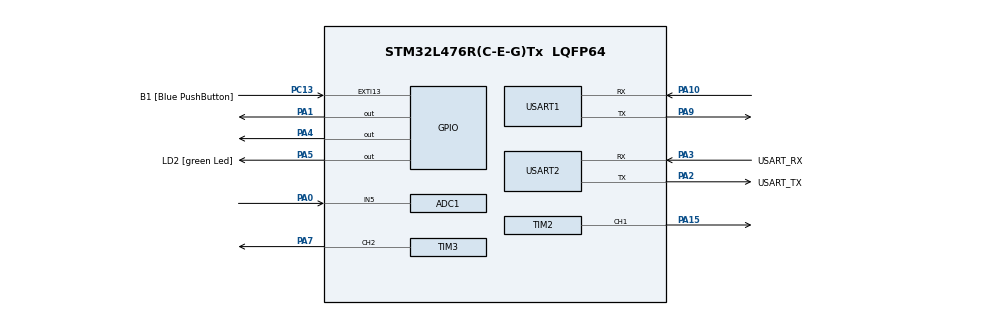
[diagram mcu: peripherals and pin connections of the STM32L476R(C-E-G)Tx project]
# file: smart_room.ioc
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ADC1.Channel-0\#ChannelRegularConversion=ADC_CHANNEL_5
ADC1.NbrOfConversionFlag=1
ADC1.OffsetNumber-0\#ChannelRegularConversion=ADC_OFFSET_NONE
ADC1.Rank-0\#ChannelRegularConversion=1
ADC1.SamplingTime-0\#ChannelRegularConversion=ADC_SAMPLETIME_2CYCLES_5
ADC1.master=1
FREERTOS.Tasks01=defaultTask,0,128,StartDefaultTask,Default,NULL,Dynamic,NULL,NULL
FREERTOS.configUSE_NEWLIB_REENTRANT=1
Mcu.Family=STM32L4
Mcu.Name=STM32L476R(C-E-G)Tx
Mcu.Package=LQFP64
NVIC.PriorityGroup=NVIC_PRIORITYGROUP_4
NVIC.TIM1_UP_TIM16_IRQn=true\:15\:0\:false\:false\:true\:false\:false\:true
NVIC.TIM2_IRQn=true\:5\:0\:false\:false\:true\:true\:true\:true
NVIC.TIM3_IRQn=true\:5\:0\:false\:false\:true\:true\:true\:true
NVIC.TimeBase=TIM1_UP_TIM16_IRQn
NVIC.TimeBaseIP=TIM1
NVIC.USART1_IRQn=true\:5\:0\:false\:false\:true\:true\:true\:true
NVIC.USART2_IRQn=true\:5\:0\:false\:false\:true\:true\:true\:true
PA0.Signal=ADCx_IN5
PA1.PinState=GPIO_PIN_SET
PA1.Signal=GPIO_Output
PA10.Mode=Asynchronous
PA10.Signal=USART1_RX
PA13\ (JTMS-SWDIO).GPIO_Label=TMS
PA13\ (JTMS-SWDIO).Mode=Serial_Wire
PA13\ (JTMS-SWDIO).Signal=SYS_JTMS-SWDIO
PA14\ (JTCK-SWCLK).GPIO_Label=TCK
PA14\ (JTCK-SWCLK).Mode=Serial_Wire
PA14\ (JTCK-SWCLK).Signal=SYS_JTCK-SWCLK
PA15\ (JTDI).Signal=S_TIM2_CH1
PA2.GPIO_Label=USART_TX
PA2.GPIO_Mode=GPIO_MODE_AF_PP
PA2.GPIO_PuPd=GPIO_NOPULL
PA2.GPIO_Speed=GPIO_SPEED_FREQ_VERY_HIGH
PA2.Mode=Asynchronous
PA2.Signal=USART2_TX
PA3.GPIO_Label=USART_RX
PA3.GPIO_Mode=GPIO_MODE_AF_PP
PA3.GPIO_PuPd=GPIO_NOPULL
PA3.GPIO_Speed=GPIO_SPEED_FREQ_VERY_HIGH
PA3.Mode=Asynchronous
PA3.Signal=USART2_RX
PA4.Signal=GPIO_Output
PA5.GPIO_Label=LD2 [green Led]
PA5.GPIO_ModeDefaultOutputPP=GPIO_MODE_OUTPUT_PP
PA5.GPIO_PuPd=GPIO_NOPULL
PA5.GPIO_Speed=GPIO_SPEED_FREQ_LOW
PA5.Signal=GPIO_Output
PA7.Signal=S_TIM3_CH2
PA9.Mode=Asynchronous
PA9.Signal=USART1_TX
PB3\ (JTDO-TRACESWO).GPIO_Label=SWO
PB3\ (JTDO-TRACESWO).Signal=SYS_JTDO-SWO
PC13.GPIO_Label=B1 [Blue PushButton]
PC13.GPIO_ModeDefaultEXTI=GPIO_MODE_IT_FALLING
PC13.GPIO_PuPd=GPIO_NOPULL
PC13.Signal=GPXTI13
PC14-OSC32_IN\ (PC14).Mode=LSE-External-Oscillator
PC14-OSC32_IN\ (PC14).Signal=RCC_OSC32_IN
PC15-OSC32_OUT\ (PC15).Mode=LSE-External-Oscillator
PC15-OSC32_OUT\ (PC15).Signal=RCC_OSC32_OUT
PH0-OSC_IN\ (PH0).Signal=RCC_OSC_IN
PH1-OSC_OUT\ (PH1).Signal=RCC_OSC_OUT
ProjectManager.HeapSize=0x200
ProjectManager.StackSize=0x400
ProjectManager.TargetToolchain=STM32CubeIDE
RCC.ADCFreq_Value=64000000
RCC.AHBCLKDivider=RCC_SYSCLK_DIV2
RCC.AHBFreq_Value=8000000
RCC.APB1Freq_Value=8000000
RCC.APB1TimFreq_Value=8000000
RCC.APB2CLKDivider=RCC_HCLK_DIV16
RCC.APB2Freq_Value=500000
RCC.APB2TimFreq_Value=1000000
RCC.CortexFreq_Value=8000000
RCC.HCLKFreq_Value=8000000
RCC.HSE_VALUE=8000000
RCC.HSI_VALUE=16000000
RCC.MSI_VALUE=4000000
RCC.PLLN=10
RCC.PLLSourceVirtual=RCC_PLLSOURCE_HSI
RCC.PREFETCH_ENABLE=1
RCC.SYSCLKFreq_VALUE=16000000
RCC.SYSCLKSource=RCC_SYSCLKSOURCE_HSI
RCC.USBFreq_Value=64000000
RCC.VCOOutputFreq_Value=160000000
SH.ADCx_IN5.0=ADC1_IN5,IN5-Single-Ended
SH.S_TIM2_CH1.0=TIM2_CH1,PWM Generation1 CH1
SH.S_TIM3_CH2.0=TIM3_CH2,PWM Generation2 CH2
TIM2.Channel-PWM\ Generation1\ CH1=TIM_CHANNEL_1
TIM2.Period=2000-1
TIM2.Prescaler=127
TIM3.Channel-PWM\ Generation2\ CH2=TIM_CHANNEL_2
TIM3.Period=1000
TIM3.Prescaler=19
TIM3.Pulse-PWM\ Generation2\ CH2=500
USART1.VirtualMode-Asynchronous=VM_ASYNC
USART2.VirtualMode-Asynchronous=VM_ASYNC
VP_FREERTOS_VS_CMSIS_V1.Mode=CMSIS_V1
VP_SYS_VS_tim1.Mode=TIM1
VP_TIM2_VS_ClockSourceINT.Mode=Internal
VP_TIM3_VS_ClockSourceINT.Mode=Internal
board=NUCLEO-L476RG

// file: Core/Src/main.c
/* USER CODE BEGIN Header */
/**
  ******************************************************************************
  * @file           : main.c
  * @brief          : Main program body
  ******************************************************************************
  * @attention
  *
  * <h2><center>&copy; Copyright (c) 2021 STMicroelectronics.
  * All rights reserved.</center></h2>
  *
  * This software component is licensed by ST under BSD 3-Clause license,
  * the "License"; You may not use this file except in compliance with the
  * License. You may obtain a copy of the License at:
  *                        opensource.org/licenses/BSD-3-Clause
  *
  ******************************************************************************
  */
/* USER CODE END Header */
#include "main.h"
#include "cmsis_os.h"

ADC_HandleTypeDef hadc1;

TIM_HandleTypeDef htim2;
TIM_HandleTypeDef htim3;

osThreadId defaultTaskHandle;

void SystemClock_Config(void);
static void MX_GPIO_Init(void);
static void MX_USART2_UART_Init(void);
static void MX_ADC1_Init(void);
static void MX_USART1_UART_Init(void);
static void MX_TIM3_Init(void);
static void MX_TIM2_Init(void);
void StartDefaultTask(void const * argument);

/* USER CODE BEGIN PFP */
void changeLedState(uint8_t mode);
int8_t readVoltage(void);
void changeDoorState(uint8_t mode);
void changeAlarmState(uint8_t mode);
/* USER CODE END PFP */

/* USER CODE BEGIN 0 */
//Tamanho das filas de transmissao e recepcao
//A fila de transmissao é maior do que a de recepcao por que a rotina de transmissao (write_string)
//pode enfileirar um numero maior de bytes de forma muito rapida
#define TX_QUEUE_SIZE 128
#define RX_QUEUE_SIZE 5
#define TIMER_MAX 200
#define USART_1 1
#define USART_2 2

//Variaveis que irao armazenar os hanldes das filas de tranmissao e recepcao
QueueHandle_t tx_queue_1;
QueueHandle_t rx_queue_1;
QueueHandle_t tx_queue_2;
QueueHandle_t rx_queue_2;
SemaphoreHandle_t uart_1_mutex = NULL;
SemaphoreHandle_t uart_2_mutex = NULL;
uint8_t door_state = 1;
uint8_t timer = 0;
uint8_t alarm_ring = 0;
uint8_t alarm_state = 0;

void sendchar(char c, char usart){
	if(usart == USART_1){
		xQueueSend(tx_queue_1, &c, HAL_MAX_DELAY);
		LL_USART_EnableIT_TXE(USART1);
	}
	else if( usart == USART_2){
		xQueueSend(tx_queue_2, &c, HAL_MAX_DELAY);
		LL_USART_EnableIT_TXE(USART2);
	}
}

void sendString(char * str, char usart){
	while(*str != 0){
		sendchar(*str, usart);
		str++;
	}
}

char readchar(char usart){
	uint8_t caracter=0;
	if(usart == USART_1)
		xQueueReceive(rx_queue_1, &caracter, HAL_MAX_DELAY);
	else if(usart == USART_2)
		xQueueReceive(rx_queue_2, &caracter, HAL_MAX_DELAY);
	return caracter;
}

void cli(void * vParam)
{
	uint8_t caracter;
	while(1)
	{
		caracter = readchar(USART_1);

		char buff[8];
		uint8_t temp = readVoltage();
		sprintf(buff,"\n%d\r\n", temp);
		sendString(buff, USART_1);

		switch(caracter){
					case 'L':
						changeLedState(1);
						break;
					case 'D':
						changeLedState(0);
						break;
					case 'O':
						changeDoorState(1);
						break;
					case 'C':
						changeDoorState(0);
						break;
					case 'A':
						changeAlarmState(1);
						break;
					case 'Z':
						changeAlarmState(0);
						break;
				}
	}

}

void changeLedState(uint8_t mode){
	HAL_GPIO_WritePin(LD2_GPIO_Port, LD2_Pin, mode);
}

void changeAlarmState(uint8_t mode){
	if(mode == 1){
		alarm_state = mode;
		timer = 1;
		HAL_TIM_Base_Start_IT(&htim2);
	} else {
		alarm_state = 0;
	}
}

int8_t readVoltage(void){
	HAL_ADC_Start(&hadc1);
	HAL_ADC_PollForConversion(&hadc1, HAL_MAX_DELAY);
	return HAL_ADC_GetValue(&hadc1) / 25;
}

void changeDoorState(uint8_t mode){
	if(mode == 1 && door_state == 0){
		HAL_TIM_PWM_Start(&htim3,TIM_CHANNEL_2);
		__HAL_TIM_SetCompare(&htim3, TIM_CHANNEL_2, 100);
		vTaskDelay(500);
		HAL_TIM_PWM_Stop(&htim3,TIM_CHANNEL_2);
		door_state = 1;

	} else if(mode == 0 && door_state == 1){
		HAL_TIM_PWM_Start(&htim3,TIM_CHANNEL_2);
		__HAL_TIM_SetCompare(&htim3, TIM_CHANNEL_2, 50);
		vTaskDelay(500);
		HAL_TIM_PWM_Stop(&htim3,TIM_CHANNEL_2);
		door_state = 0;
	}
}

//Rotina de tratamento de interrupcao da USART2
void USART_2_IRQHandler(void)
{
	//Se for interrupcao de transmissao
    if (LL_USART_IsActiveFlag_TXE(USART2)) {
        BaseType_t contextSwitch;

        while (LL_USART_IsActiveFlag_TXE(USART2)) {
            uint8_t byte;
            //Desinfileira um byte para tranmistir
            if (xQueueReceiveFromISR(tx_queue_2, &byte, &contextSwitch) == pdFAIL) {
            	//Se a fila de transmissao esta vazia, encerra a transmissao
                LL_USART_DisableIT_TXE(USART2);
                break;
            }
            //Envia o byte retirado da fila de transmisao
            LL_USART_TransmitData8(USART2, byte);
        }
        portYIELD_FROM_ISR(contextSwitch);
    }

    //Se for interrupcao de recepcao
    if (LL_USART_IsActiveFlag_RXNE(USART2)) {
        BaseType_t contextSwitch;

        while (LL_USART_IsActiveFlag_RXNE(USART2)) {
        	//Copia o byte do regstrador de recepcao
        	uint8_t byte =
                LL_USART_ReceiveData8(USART2);
        	//Enfileira o byte recebido na fila de recepcao
            xQueueSendFromISR(rx_queue_2, &byte, &contextSwitch);
            // xQueueSendFromISR can return errQUEUE_FULL
        }
        portYIELD_FROM_ISR(contextSwitch);
    }
}

void USART_1_IRQHandler(void)
{
	//Se for interrupcao de transmissao
    if (LL_USART_IsActiveFlag_TXE(USART1)) {
        BaseType_t contextSwitch;

        while (LL_USART_IsActiveFlag_TXE(USART1)) {
            uint8_t byte;
            //Desinfileira um byte para tranmistir
            if (xQueueReceiveFromISR(tx_queue_1, &byte, &contextSwitch) == pdFAIL) {
            	//Se a fila de transmissao esta vazia, encerra a transmissao
                LL_USART_DisableIT_TXE(USART1);
                break;
            }
            //Envia o byte retirado da fila de transmisao
            LL_USART_TransmitData8(USART1, byte);
        }
        portYIELD_FROM_ISR(contextSwitch);
    }

    //Se for interrupcao de recepcao
    if (LL_USART_IsActiveFlag_RXNE(USART1)) {
        BaseType_t contextSwitch;

        while (LL_USART_IsActiveFlag_RXNE(USART1)) {
        	//Copia o byte do regstrador de recepcao
        	uint8_t byte =
                LL_USART_ReceiveData8(USART1);
        	//Enfileira o byte recebido na fila de recepcao
            xQueueSendFromISR(rx_queue_1, &byte, &contextSwitch);
            // xQueueSendFromISR can return errQUEUE_FULL
        }
        portYIELD_FROM_ISR(contextSwitch);
    }
}
/* USER CODE END 0 */

int main(void)
{

  /* MCU Configuration--------------------------------------------------------*/

  /* Reset of all peripherals, Initializes the Flash interface and the Systick. */
  HAL_Init();

  /* Configure the system clock */
  SystemClock_Config();

  /* Initialize all configured peripherals */
  MX_GPIO_Init();
  MX_USART2_UART_Init();
  MX_ADC1_Init();
  MX_USART1_UART_Init();
  MX_TIM3_Init();
  MX_TIM2_Init();
  /* USER CODE BEGIN 2 */
  uart_1_mutex = xSemaphoreCreateMutex();
  uart_2_mutex = xSemaphoreCreateMutex();

  HAL_TIM_Base_Start(&htim3);

  /* USER CODE END 2 */

  /* Create the thread(s) */
  /* definition and creation of defaultTask */
  osThreadDef(defaultTask, StartDefaultTask, osPriorityNormal, 0, 128);
  defaultTaskHandle = osThreadCreate(osThread(defaultTask), NULL);

  /* USER CODE BEGIN RTOS_THREADS */
  xTaskCreate(cli,    /* Nome da funcao que contem a task */
  		  	  "cli",     /* Nome descritivo */
			  configMINIMAL_STACK_SIZE,   /* tamanho da pilha da task */
			  NULL,       /* parametro para a task */
			  1,          /* nivel de prioridade */
			  NULL);      /* ponteiro para o handle da task */

  /* USER CODE END RTOS_THREADS */

  /* Start scheduler */
  osKernelStart();

  /* We should never get here as control is now taken by the scheduler */
  /* Infinite loop */
  while (1)
  {

  }
}

void SystemClock_Config(void)
{
  RCC_OscInitTypeDef RCC_OscInitStruct = {0};
  RCC_ClkInitTypeDef RCC_ClkInitStruct = {0};

  /** Configure the main internal regulator output voltage
  */
  if (HAL_PWREx_ControlVoltageScaling(PWR_REGULATOR_VOLTAGE_SCALE1) != HAL_OK)
  {
    Error_Handler();
  }
  /** Initializes the RCC Oscillators according to the specified parameters
  * in the RCC_OscInitTypeDef structure.
  */
  RCC_OscInitStruct.OscillatorType = RCC_OSCILLATORTYPE_HSI;
  RCC_OscInitStruct.HSIState = RCC_HSI_ON;
  RCC_OscInitStruct.HSICalibrationValue = RCC_HSICALIBRATION_DEFAULT;
  RCC_OscInitStruct.PLL.PLLState = RCC_PLL_ON;
  RCC_OscInitStruct.PLL.PLLSource = RCC_PLLSOURCE_HSI;
  RCC_OscInitStruct.PLL.PLLM = 1;
  RCC_OscInitStruct.PLL.PLLN = 10;
  RCC_OscInitStruct.PLL.PLLP = RCC_PLLP_DIV7;
  RCC_OscInitStruct.PLL.PLLQ = RCC_PLLQ_DIV2;
  RCC_OscInitStruct.PLL.PLLR = RCC_PLLR_DIV2;
  if (HAL_RCC_OscConfig(&RCC_OscInitStruct) != HAL_OK)
  {
    Error_Handler();
  }
  /** Initializes the CPU, AHB and APB buses clocks
  */
  RCC_ClkInitStruct.ClockType = RCC_CLOCKTYPE_HCLK|RCC_CLOCKTYPE_SYSCLK
                              |RCC_CLOCKTYPE_PCLK1|RCC_CLOCKTYPE_PCLK2;
  RCC_ClkInitStruct.SYSCLKSource = RCC_SYSCLKSOURCE_PLLCLK;
  RCC_ClkInitStruct.AHBCLKDivider = RCC_SYSCLK_DIV1;
  RCC_ClkInitStruct.APB1CLKDivider = RCC_HCLK_DIV1;
  RCC_ClkInitStruct.APB2CLKDivider = RCC_HCLK_DIV1;

  if (HAL_RCC_ClockConfig(&RCC_ClkInitStruct, FLASH_LATENCY_4) != HAL_OK)
  {
    Error_Handler();
  }
}

static void MX_ADC1_Init(void)
{

  ADC_MultiModeTypeDef multimode = {0};
  ADC_ChannelConfTypeDef sConfig = {0};

  /** Common config
  */
  hadc1.Instance = ADC1;
  hadc1.Init.ClockPrescaler = ADC_CLOCK_ASYNC_DIV1;
  hadc1.Init.Resolution = ADC_RESOLUTION_12B;
  hadc1.Init.DataAlign = ADC_DATAALIGN_RIGHT;
  hadc1.Init.ScanConvMode = ADC_SCAN_DISABLE;
  hadc1.Init.EOCSelection = ADC_EOC_SINGLE_CONV;
  hadc1.Init.LowPowerAutoWait = DISABLE;
  hadc1.Init.ContinuousConvMode = DISABLE;
  hadc1.Init.NbrOfConversion = 1;
  hadc1.Init.DiscontinuousConvMode = DISABLE;
  hadc1.Init.ExternalTrigConv = ADC_SOFTWARE_START;
  hadc1.Init.ExternalTrigConvEdge = ADC_EXTERNALTRIGCONVEDGE_NONE;
  hadc1.Init.DMAContinuousRequests = DISABLE;
  hadc1.Init.Overrun = ADC_OVR_DATA_PRESERVED;
  hadc1.Init.OversamplingMode = DISABLE;
  if (HAL_ADC_Init(&hadc1) != HAL_OK)
  {
    Error_Handler();
  }
  /** Configure the ADC multi-mode
  */
  multimode.Mode = ADC_MODE_INDEPENDENT;
  if (HAL_ADCEx_MultiModeConfigChannel(&hadc1, &multimode) != HAL_OK)
  {
    Error_Handler();
  }
  /** Configure Regular Channel
  */
  sConfig.Channel = ADC_CHANNEL_5;
  sConfig.Rank = ADC_REGULAR_RANK_1;
  sConfig.SamplingTime = ADC_SAMPLETIME_2CYCLES_5;
  sConfig.SingleDiff = ADC_SINGLE_ENDED;
  sConfig.OffsetNumber = ADC_OFFSET_NONE;
  sConfig.Offset = 0;
  if (HAL_ADC_ConfigChannel(&hadc1, &sConfig) != HAL_OK)
  {
    Error_Handler();
  }

}

static void MX_TIM2_Init(void)
{

  TIM_ClockConfigTypeDef sClockSourceConfig = {0};
  TIM_MasterConfigTypeDef sMasterConfig = {0};
  TIM_OC_InitTypeDef sConfigOC = {0};

  htim2.Instance = TIM2;
  htim2.Init.Prescaler = 127;
  htim2.Init.CounterMode = TIM_COUNTERMODE_UP;
  htim2.Init.Period = 2000-1;
  htim2.Init.ClockDivision = TIM_CLOCKDIVISION_DIV1;
  htim2.Init.AutoReloadPreload = TIM_AUTORELOAD_PRELOAD_DISABLE;
  if (HAL_TIM_Base_Init(&htim2) != HAL_OK)
  {
    Error_Handler();
  }
  sClockSourceConfig.ClockSource = TIM_CLOCKSOURCE_INTERNAL;
  if (HAL_TIM_ConfigClockSource(&htim2, &sClockSourceConfig) != HAL_OK)
  {
    Error_Handler();
  }
  if (HAL_TIM_PWM_Init(&htim2) != HAL_OK)
  {
    Error_Handler();
  }
  sMasterConfig.MasterOutputTrigger = TIM_TRGO_RESET;
  sMasterConfig.MasterSlaveMode = TIM_MASTERSLAVEMODE_DISABLE;
  if (HAL_TIMEx_MasterConfigSynchronization(&htim2, &sMasterConfig) != HAL_OK)
  {
    Error_Handler();
  }
  sConfigOC.OCMode = TIM_OCMODE_PWM1;
  sConfigOC.Pulse = 0;
  sConfigOC.OCPolarity = TIM_OCPOLARITY_HIGH;
  sConfigOC.OCFastMode = TIM_OCFAST_DISABLE;
  if (HAL_TIM_PWM_ConfigChannel(&htim2, &sConfigOC, TIM_CHANNEL_1) != HAL_OK)
  {
    Error_Handler();
  }
  HAL_TIM_MspPostInit(&htim2);

}

static void MX_TIM3_Init(void)
{

  TIM_ClockConfigTypeDef sClockSourceConfig = {0};
  TIM_MasterConfigTypeDef sMasterConfig = {0};
  TIM_OC_InitTypeDef sConfigOC = {0};

  htim3.Instance = TIM3;
  htim3.Init.Prescaler = 19;
  htim3.Init.CounterMode = TIM_COUNTERMODE_UP;
  htim3.Init.Period = 1000;
  htim3.Init.ClockDivision = TIM_CLOCKDIVISION_DIV1;
  htim3.Init.AutoReloadPreload = TIM_AUTORELOAD_PRELOAD_DISABLE;
  if (HAL_TIM_Base_Init(&htim3) != HAL_OK)
  {
    Error_Handler();
  }
  sClockSourceConfig.ClockSource = TIM_CLOCKSOURCE_INTERNAL;
  if (HAL_TIM_ConfigClockSource(&htim3, &sClockSourceConfig) != HAL_OK)
  {
    Error_Handler();
  }
  if (HAL_TIM_PWM_Init(&htim3) != HAL_OK)
  {
    Error_Handler();
  }
  sMasterConfig.MasterOutputTrigger = TIM_TRGO_RESET;
  sMasterConfig.MasterSlaveMode = TIM_MASTERSLAVEMODE_DISABLE;
  if (HAL_TIMEx_MasterConfigSynchronization(&htim3, &sMasterConfig) != HAL_OK)
  {
    Error_Handler();
  }
  sConfigOC.OCMode = TIM_OCMODE_PWM1;
  sConfigOC.Pulse = 500;
  sConfigOC.OCPolarity = TIM_OCPOLARITY_HIGH;
  sConfigOC.OCFastMode = TIM_OCFAST_DISABLE;
  if (HAL_TIM_PWM_ConfigChannel(&htim3, &sConfigOC, TIM_CHANNEL_2) != HAL_OK)
  {
    Error_Handler();
  }
  HAL_TIM_MspPostInit(&htim3);

}

static void MX_USART1_UART_Init(void)
{

  LL_USART_InitTypeDef USART_InitStruct = {0};

  LL_GPIO_InitTypeDef GPIO_InitStruct = {0};
  RCC_PeriphCLKInitTypeDef PeriphClkInit = {0};

  /** Initializes the peripherals clock
  */
  PeriphClkInit.PeriphClockSelection = RCC_PERIPHCLK_USART1;
  PeriphClkInit.Usart1ClockSelection = RCC_USART1CLKSOURCE_PCLK2;
  if (HAL_RCCEx_PeriphCLKConfig(&PeriphClkInit) != HAL_OK)
  {
    Error_Handler();
  }

  /* Peripheral clock enable */
  LL_APB2_GRP1_EnableClock(LL_APB2_GRP1_PERIPH_USART1);

  LL_AHB2_GRP1_EnableClock(LL_AHB2_GRP1_PERIPH_GPIOA);
  /**USART1 GPIO Configuration
  PA9   ------> USART1_TX
  PA10   ------> USART1_RX
  */
  GPIO_InitStruct.Pin = LL_GPIO_PIN_9|LL_GPIO_PIN_10;
  GPIO_InitStruct.Mode = LL_GPIO_MODE_ALTERNATE;
  GPIO_InitStruct.Speed = LL_GPIO_SPEED_FREQ_VERY_HIGH;
  GPIO_InitStruct.OutputType = LL_GPIO_OUTPUT_PUSHPULL;
  GPIO_InitStruct.Pull = LL_GPIO_PULL_NO;
  GPIO_InitStruct.Alternate = LL_GPIO_AF_7;
  LL_GPIO_Init(GPIOA, &GPIO_InitStruct);

  /* USART1 interrupt Init */
  NVIC_SetPriority(USART1_IRQn, NVIC_EncodePriority(NVIC_GetPriorityGrouping(),5, 0));
  NVIC_EnableIRQ(USART1_IRQn);

  USART_InitStruct.BaudRate = 115200;
  USART_InitStruct.DataWidth = LL_USART_DATAWIDTH_8B;
  USART_InitStruct.StopBits = LL_USART_STOPBITS_1;
  USART_InitStruct.Parity = LL_USART_PARITY_NONE;
  USART_InitStruct.TransferDirection = LL_USART_DIRECTION_TX_RX;
  USART_InitStruct.HardwareFlowControl = LL_USART_HWCONTROL_NONE;
  USART_InitStruct.OverSampling = LL_USART_OVERSAMPLING_16;
  LL_USART_Init(USART1, &USART_InitStruct);
  LL_USART_ConfigAsyncMode(USART1);
  LL_USART_Enable(USART1);
  /* USER CODE BEGIN USART1_Init 2 */
  //Inicializa as filas de transmissao e recepcao
   tx_queue_1 = xQueueCreate(TX_QUEUE_SIZE, sizeof(uint8_t));
   rx_queue_1 = xQueueCreate(RX_QUEUE_SIZE, sizeof(uint8_t));
   //Habilita a interrupcao de recepcao pela USART2
   LL_USART_EnableIT_RXNE(USART1);
  /* USER CODE END USART1_Init 2 */

}

static void MX_USART2_UART_Init(void)
{

  LL_USART_InitTypeDef USART_InitStruct = {0};

  LL_GPIO_InitTypeDef GPIO_InitStruct = {0};
  RCC_PeriphCLKInitTypeDef PeriphClkInit = {0};

  /** Initializes the peripherals clock
  */
  PeriphClkInit.PeriphClockSelection = RCC_PERIPHCLK_USART2;
  PeriphClkInit.Usart2ClockSelection = RCC_USART2CLKSOURCE_PCLK1;
  if (HAL_RCCEx_PeriphCLKConfig(&PeriphClkInit) != HAL_OK)
  {
    Error_Handler();
  }

  /* Peripheral clock enable */
  LL_APB1_GRP1_EnableClock(LL_APB1_GRP1_PERIPH_USART2);

  LL_AHB2_GRP1_EnableClock(LL_AHB2_GRP1_PERIPH_GPIOA);
  /**USART2 GPIO Configuration
  PA2   ------> USART2_TX
  PA3   ------> USART2_RX
  */
  GPIO_InitStruct.Pin = LL_GPIO_PIN_2|LL_GPIO_PIN_3;
  GPIO_InitStruct.Mode = LL_GPIO_MODE_ALTERNATE;
  GPIO_InitStruct.Speed = LL_GPIO_SPEED_FREQ_VERY_HIGH;
  GPIO_InitStruct.OutputType = LL_GPIO_OUTPUT_PUSHPULL;
  GPIO_InitStruct.Pull = LL_GPIO_PULL_NO;
  GPIO_InitStruct.Alternate = LL_GPIO_AF_7;
  LL_GPIO_Init(GPIOA, &GPIO_InitStruct);

  /* USART2 interrupt Init */
  NVIC_SetPriority(USART2_IRQn, NVIC_EncodePriority(NVIC_GetPriorityGrouping(),5, 0));
  NVIC_EnableIRQ(USART2_IRQn);

  USART_InitStruct.BaudRate = 115200;
  USART_InitStruct.DataWidth = LL_USART_DATAWIDTH_8B;
  USART_InitStruct.StopBits = LL_USART_STOPBITS_1;
  USART_InitStruct.Parity = LL_USART_PARITY_NONE;
  USART_InitStruct.TransferDirection = LL_USART_DIRECTION_TX_RX;
  USART_InitStruct.HardwareFlowControl = LL_USART_HWCONTROL_NONE;
  USART_InitStruct.OverSampling = LL_USART_OVERSAMPLING_16;
  LL_USART_Init(USART2, &USART_InitStruct);
  LL_USART_ConfigAsyncMode(USART2);
  LL_USART_Enable(USART2);
  /* USER CODE BEGIN USART2_Init 2 */
  //Inicializa as filas de transmissao e recepcao
   tx_queue_2 = xQueueCreate(TX_QUEUE_SIZE, sizeof(uint8_t));
   rx_queue_2 = xQueueCreate(RX_QUEUE_SIZE, sizeof(uint8_t));
   //Habilita a interrupcao de recepcao pela USART2
   LL_USART_EnableIT_RXNE(USART2);
  /* USER CODE END USART2_Init 2 */

}

static void MX_GPIO_Init(void)
{
  GPIO_InitTypeDef GPIO_InitStruct = {0};

  /* GPIO Ports Clock Enable */
  __HAL_RCC_GPIOC_CLK_ENABLE();
  __HAL_RCC_GPIOH_CLK_ENABLE();
  __HAL_RCC_GPIOA_CLK_ENABLE();
  __HAL_RCC_GPIOB_CLK_ENABLE();

  /*Configure GPIO pin Output Level */
  HAL_GPIO_WritePin(GPIOA, GPIO_PIN_1|GPIO_PIN_4|LD2_Pin, GPIO_PIN_RESET);

  /*Configure GPIO pin : B1_Pin */
  GPIO_InitStruct.Pin = B1_Pin;
  GPIO_InitStruct.Mode = GPIO_MODE_IT_FALLING;
  GPIO_InitStruct.Pull = GPIO_NOPULL;
  HAL_GPIO_Init(B1_GPIO_Port, &GPIO_InitStruct);

  /*Configure GPIO pins : PA1 PA4 LD2_Pin */
  GPIO_InitStruct.Pin = GPIO_PIN_1|GPIO_PIN_4|LD2_Pin;
  GPIO_InitStruct.Mode = GPIO_MODE_OUTPUT_PP;
  GPIO_InitStruct.Pull = GPIO_NOPULL;
  GPIO_InitStruct.Speed = GPIO_SPEED_FREQ_LOW;
  HAL_GPIO_Init(GPIOA, &GPIO_InitStruct);

}

void StartDefaultTask(void const * argument)
{
  for(;;)
  {
    osDelay(1);
  }
}

void HAL_TIM_PeriodElapsedCallback(TIM_HandleTypeDef *htim)
{
  if (htim->Instance == htim2.Instance && alarm_state == 1 && timer >= 1) {
	  if(timer <= 20){
		  timer++;
	  } else {
			HAL_GPIO_TogglePin(LD2_GPIO_Port, LD2_Pin);
			HAL_TIM_Base_Stop_IT(&htim2);
			timer = 0;
	  }
  }
}

void Error_Handler(void)
{
  __disable_irq();
  while (1)
  {
  }
}

/************************ (C) COPYRIGHT STMicroelectronics *****END OF FILE****/
